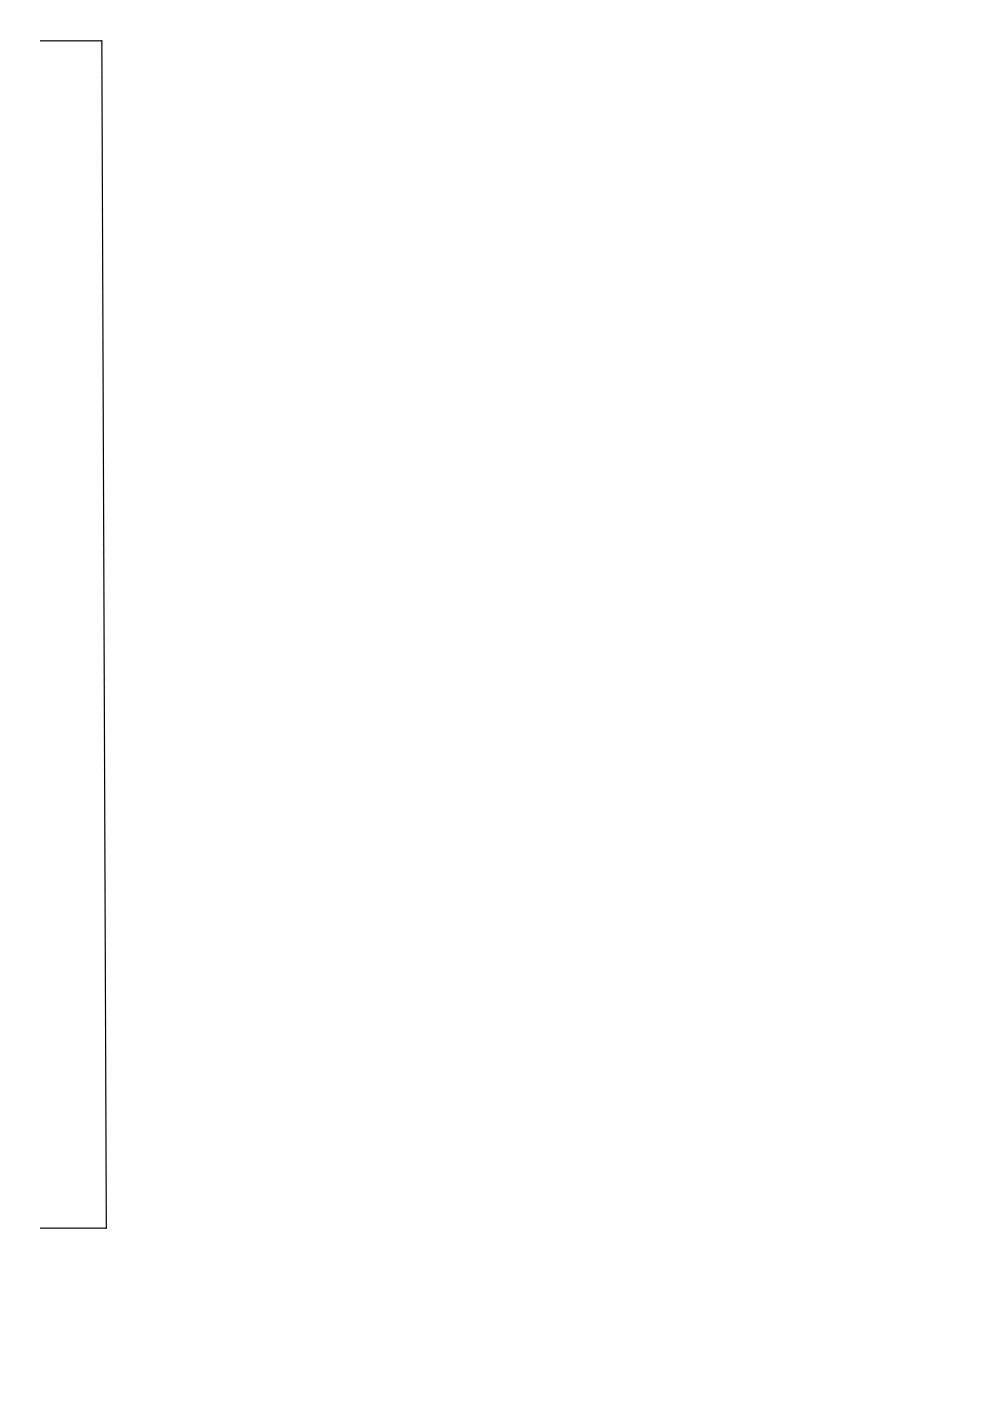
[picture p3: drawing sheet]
<svg xmlns="http://www.w3.org/2000/svg" width="210mm" height="297mm" viewBox="0 0 210 297" stroke-linecap="round" stroke-linejoin="round" font-family="sans-serif">
<path d="M8.5 8.7h13.1l.9 251.7h-14" fill="none" stroke="#000" stroke-width=".25"/>
</svg>
